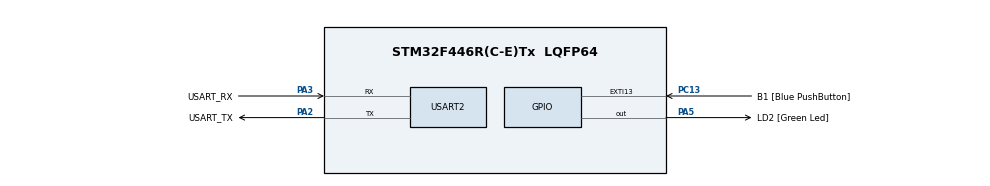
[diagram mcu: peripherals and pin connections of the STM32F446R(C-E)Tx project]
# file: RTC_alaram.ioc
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Mcu.Family=STM32F4
Mcu.Name=STM32F446R(C-E)Tx
Mcu.Package=LQFP64
NVIC.PriorityGroup=NVIC_PRIORITYGROUP_0
NVIC.RTC_Alarm_IRQn=true\:0\:0\:false\:false\:true\:true\:true\:true
PA13.GPIO_Label=TMS
PA13.Mode=Serial_Wire
PA13.Signal=SYS_JTMS-SWDIO
PA14.GPIO_Label=TCK
PA14.Mode=Serial_Wire
PA14.Signal=SYS_JTCK-SWCLK
PA2.GPIO_Label=USART_TX
PA2.Mode=Asynchronous
PA2.Signal=USART2_TX
PA3.GPIO_Label=USART_RX
PA3.Mode=Asynchronous
PA3.Signal=USART2_RX
PA5.GPIO_Label=LD2 [Green Led]
PA5.Signal=GPIO_Output
PB3.GPIO_Label=SWO
PB3.Signal=SYS_JTDO-SWO
PC13.GPIO_Label=B1 [Blue PushButton]
PC13.GPIO_ModeDefaultEXTI=GPIO_MODE_IT_FALLING
PC13.Signal=GPXTI13
PC14-OSC32_IN.Mode=LSE-External-Oscillator
PC14-OSC32_IN.Signal=RCC_OSC32_IN
PC15-OSC32_OUT.Mode=LSE-External-Oscillator
PC15-OSC32_OUT.Signal=RCC_OSC32_OUT
PH0-OSC_IN.Mode=HSE-External-Oscillator
PH0-OSC_IN.Signal=RCC_OSC_IN
PH1-OSC_OUT.Mode=HSE-External-Oscillator
PH1-OSC_OUT.Signal=RCC_OSC_OUT
ProjectManager.HeapSize=0x200
ProjectManager.StackSize=0x400
ProjectManager.TargetToolchain=STM32CubeIDE
RCC.48MHZClocksFreq_Value=84000000
RCC.AHBFreq_Value=80000000
RCC.APB1CLKDivider=RCC_HCLK_DIV2
RCC.APB1Freq_Value=40000000
RCC.APB1TimFreq_Value=80000000
RCC.APB2Freq_Value=80000000
RCC.APB2TimFreq_Value=80000000
RCC.CortexFreq_Value=80000000
RCC.FLatency-AdvancedSettings=FLASH_LATENCY_2
RCC.HCLKFreq_Value=80000000
RCC.HSE_VALUE=8000000
RCC.HSI_VALUE=16000000
RCC.PLLM=4
RCC.PLLN=80
RCC.PLLSourceVirtual=RCC_PLLSOURCE_HSE
RCC.RCC_RTC_Clock_SourceVirtual=RCC_RTCCLKSOURCE_LSE
RCC.SYSCLKFreq_VALUE=80000000
RCC.SYSCLKSource=RCC_SYSCLKSOURCE_PLLCLK
RCC.USBFreq_Value=80000000
RCC.VCOOutputFreq_Value=160000000
RTC.Alarm=RTC_ALARM_A
RTC.Date=24
RTC.Format=RTC_FORMAT_BIN
RTC.Hours=11
RTC.Hours_A=12
RTC.Minutes=46
RTC.Month=RTC_MONTH_SEPTEMBER
RTC.WeekDay=RTC_WEEKDAY_WEDNESDAY
RTC.Year=25
USART2.VirtualMode=VM_ASYNC
VP_RTC_VS_RTC_Activate.Mode=RTC_Enabled
VP_RTC_VS_RTC_Alarm_A_Intern.Mode=Alarm A
VP_RTC_VS_RTC_Calendar.Mode=RTC_Calendar
board=NUCLEO-F446RE

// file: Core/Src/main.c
/* USER CODE BEGIN Header */
/**
  ******************************************************************************
  * @file           : main.c
  * @brief          : Main program body
  ******************************************************************************
  * @attention
  *
  * Copyright (c) 2024 STMicroelectronics.
  * All rights reserved.
  *
  * This software is licensed under terms that can be found in the LICENSE file
  * in the root directory of this software component.
  * If no LICENSE file comes with this software, it is provided AS-IS.
  *
  ******************************************************************************
  */
/* USER CODE END Header */
#include "main.h"
#include <stdio.h>
#include <string.h>

RTC_HandleTypeDef hrtc;

UART_HandleTypeDef huart2;

/* USER CODE BEGIN PV */
uint8_t previous_hour = 0xFF; // Initialize to invalid value for midnight detection
/* USER CODE END PV */

void SystemClock_Config(void);
static void MX_GPIO_Init(void);
static void MX_RTC_Init(void);
static void MX_USART2_UART_Init(void);
/* USER CODE BEGIN PFP */
void UART_Transmit_String(char* str);
/* USER CODE END PFP */

int main(void)
{

  /* MCU Configuration--------------------------------------------------------*/

  /* Reset of all peripherals, Initializes the Flash interface and the Systick. */
  HAL_Init();

  /* Configure the system clock */
  SystemClock_Config();

  /* Initialize all configured peripherals */
  MX_GPIO_Init();
  MX_RTC_Init();
  MX_USART2_UART_Init();
  /* USER CODE BEGIN 2 */

  // Send initial message
  UART_Transmit_String("RTC System Initialized\r\n");

  // Get initial hour for midnight detection
  RTC_TimeTypeDef sTime;
  HAL_RTC_GetTime(&hrtc, &sTime, RTC_FORMAT_BIN);
  previous_hour = sTime.Hours;

  /* USER CODE END 2 */

  /* Infinite loop */
  while (1)
  {

    /* USER CODE BEGIN 3 */
    // Check for midnight rollover in main loop
    RTC_TimeTypeDef current_time;
    HAL_RTC_GetTime(&hrtc, &current_time, RTC_FORMAT_BIN);

    // Detect midnight rollover (23:XX:XX -> 00:XX:XX)
    if (previous_hour == 23 && current_time.Hours == 0) {
        UART_Transmit_String("New Day Started!\r\n");
    }
    previous_hour = current_time.Hours;

    // Enter sleep mode to save power
    HAL_PWR_EnterSLEEPMode(PWR_MAINREGULATOR_ON, PWR_SLEEPENTRY_WFI);
  }
  /* USER CODE END 3 */
}

void SystemClock_Config(void)
{
  RCC_OscInitTypeDef RCC_OscInitStruct = {0};
  RCC_ClkInitTypeDef RCC_ClkInitStruct = {0};
  RCC_PeriphCLKInitTypeDef PeriphClkInitStruct = {0};

  /** Configure the main internal regulator output voltage
  */
  __HAL_RCC_PWR_CLK_ENABLE();
  __HAL_PWR_VOLTAGESCALING_CONFIG(PWR_REGULATOR_VOLTAGE_SCALE3);

  /** Initializes the RCC Oscillators according to the specified parameters
  * in the RCC_OscInitTypeDef structure.
  */
  RCC_OscInitStruct.OscillatorType = RCC_OSCILLATORTYPE_HSI|RCC_OSCILLATORTYPE_LSI;
  RCC_OscInitStruct.HSIState = RCC_HSI_ON;
  RCC_OscInitStruct.HSICalibrationValue = RCC_HSICALIBRATION_DEFAULT;
  RCC_OscInitStruct.LSIState = RCC_LSI_ON;
  RCC_OscInitStruct.PLL.PLLState = RCC_PLL_ON;
  RCC_OscInitStruct.PLL.PLLSource = RCC_PLLSOURCE_HSI;
  RCC_OscInitStruct.PLL.PLLM = 16;
  RCC_OscInitStruct.PLL.PLLN = 336;
  RCC_OscInitStruct.PLL.PLLP = RCC_PLLP_DIV4;
  RCC_OscInitStruct.PLL.PLLQ = 4;
  if (HAL_RCC_OscConfig(&RCC_OscInitStruct) != HAL_OK)
  {
    Error_Handler();
  }

  /** Initializes the CPU, AHB and APB buses clocks
  */
  RCC_ClkInitStruct.ClockType = RCC_CLOCKTYPE_HCLK|RCC_CLOCKTYPE_SYSCLK
                              |RCC_CLOCKTYPE_PCLK1|RCC_CLOCKTYPE_PCLK2;
  RCC_ClkInitStruct.SYSCLKSource = RCC_SYSCLKSOURCE_PLLCLK;
  RCC_ClkInitStruct.AHBCLKDivider = RCC_SYSCLK_DIV1;
  RCC_ClkInitStruct.APB1CLKDivider = RCC_HCLK_DIV2;
  RCC_ClkInitStruct.APB2CLKDivider = RCC_HCLK_DIV1;

  if (HAL_RCC_ClockConfig(&RCC_ClkInitStruct, FLASH_LATENCY_2) != HAL_OK)
  {
    Error_Handler();
  }

  /** PeriphClkInitStruct.PeriphClockSelection = RTC
  */
  PeriphClkInitStruct.PeriphClockSelection = RCC_PERIPHCLK_RTC;
  PeriphClkInitStruct.RTCClockSelection = RCC_RTCCLKSOURCE_LSI;
  if (HAL_RCCEx_PeriphCLKConfig(&PeriphClkInitStruct) != HAL_OK)
  {
    Error_Handler();
  }
}

static void MX_RTC_Init(void)
{

  RTC_TimeTypeDef sTime = {0};
  RTC_DateTypeDef sDate = {0};
  RTC_AlarmTypeDef sAlarm = {0};

  /** Initialize RTC Only
  */
  hrtc.Instance = RTC;
  hrtc.Init.HourFormat = RTC_HOURFORMAT_24;
  hrtc.Init.AsynchPrediv = 127;
  hrtc.Init.SynchPrediv = 255;
  hrtc.Init.OutPut = RTC_OUTPUT_DISABLE;
  hrtc.Init.OutPutPolarity = RTC_OUTPUT_POLARITY_HIGH;
  hrtc.Init.OutPutType = RTC_OUTPUT_TYPE_OPENDRAIN;
  if (HAL_RTC_Init(&hrtc) != HAL_OK)
  {
    Error_Handler();
  }

  /** Initialize RTC and set the Time and Date
  */
  sTime.Hours = 0x12;
  sTime.Minutes = 0x29;
  sTime.Seconds = 0x55;
  sTime.DayLightSaving = RTC_DAYLIGHTSAVING_NONE;
  sTime.StoreOperation = RTC_STOREOPERATION_RESET;
  if (HAL_RTC_SetTime(&hrtc, &sTime, RTC_FORMAT_BCD) != HAL_OK)
  {
    Error_Handler();
  }
  sDate.WeekDay = RTC_WEEKDAY_MONDAY;
  sDate.Month = RTC_MONTH_JANUARY;
  sDate.Date = 0x1;
  sDate.Year = 0x24;

  if (HAL_RTC_SetDate(&hrtc, &sDate, RTC_FORMAT_BCD) != HAL_OK)
  {
    Error_Handler();
  }

  /** Enable the Alarm A
  */
  sAlarm.AlarmTime.Hours = 0x12;
  sAlarm.AlarmTime.Minutes = 0x30;
  sAlarm.AlarmTime.Seconds = 0x0;
  sAlarm.AlarmTime.SubSeconds = 0x0;
  sAlarm.AlarmTime.DayLightSaving = RTC_DAYLIGHTSAVING_NONE;
  sAlarm.AlarmTime.StoreOperation = RTC_STOREOPERATION_RESET;
  sAlarm.AlarmMask = RTC_ALARMMASK_DATEWEEKDAY;
  sAlarm.AlarmSubSecondMask = RTC_ALARMSUBSECONDMASK_ALL;
  sAlarm.AlarmDateWeekDaySel = RTC_ALARMDATEWEEKDAYSEL_DATE;
  sAlarm.AlarmDateWeekDay = 0x1;
  sAlarm.Alarm = RTC_ALARM_A;
  if (HAL_RTC_SetAlarm_IT(&hrtc, &sAlarm, RTC_FORMAT_BCD) != HAL_OK)
  {
    Error_Handler();
  }

  /** Enable the WakeUp
  */
  if (HAL_RTCEx_SetWakeUpTimer_IT(&hrtc, 3999, RTC_WAKEUPCLOCK_RTCCLK_DIV16) != HAL_OK)
  {
    Error_Handler();
  }

}

static void MX_USART2_UART_Init(void)
{

  huart2.Instance = USART2;
  huart2.Init.BaudRate = 115200;
  huart2.Init.WordLength = UART_WORDLENGTH_8B;
  huart2.Init.StopBits = UART_STOPBITS_1;
  huart2.Init.Parity = UART_PARITY_NONE;
  huart2.Init.Mode = UART_MODE_TX_RX;
  huart2.Init.HwFlowCtl = UART_HWCONTROL_NONE;
  huart2.Init.OverSampling = UART_OVERSAMPLING_16;
  if (HAL_UART_Init(&huart2) != HAL_OK)
  {
    Error_Handler();
  }

}

static void MX_GPIO_Init(void)
{
  GPIO_InitTypeDef GPIO_InitStruct = {0};

  /* GPIO Ports Clock Enable */
  __HAL_RCC_GPIOC_CLK_ENABLE();
  __HAL_RCC_GPIOH_CLK_ENABLE();
  __HAL_RCC_GPIOA_CLK_ENABLE();
  __HAL_RCC_GPIOB_CLK_ENABLE();

  /*Configure GPIO pin Output Level */
  HAL_GPIO_WritePin(LD2_GPIO_Port, LD2_Pin, GPIO_PIN_RESET);

  /*Configure GPIO pin : B1_Pin */
  GPIO_InitStruct.Pin = B1_Pin;
  GPIO_InitStruct.Mode = GPIO_MODE_IT_FALLING;
  GPIO_InitStruct.Pull = GPIO_NOPULL;
  HAL_GPIO_Init(B1_GPIO_Port, &GPIO_InitStruct);

  /*Configure GPIO pin : LD2_Pin */
  GPIO_InitStruct.Pin = LD2_Pin;
  GPIO_InitStruct.Mode = GPIO_MODE_OUTPUT_PP;
  GPIO_InitStruct.Pull = GPIO_NOPULL;
  GPIO_InitStruct.Speed = GPIO_SPEED_FREQ_LOW;
  HAL_GPIO_Init(LD2_GPIO_Port, &GPIO_InitStruct);

}

/* USER CODE BEGIN 4 */

/**
  * @brief  UART Transmit String Function
  * @param  str: String to transmit
  * @retval None
  */
void UART_Transmit_String(char* str)
{
    HAL_UART_Transmit(&huart2, (uint8_t*)str, strlen(str), HAL_MAX_DELAY);
}

/**
  * @brief  RTC WakeUp Timer Event Callback
  * @param  hrtc: RTC handle pointer
  * @retval None
  */
void HAL_RTCEx_WakeUpTimerEventCallback(RTC_HandleTypeDef *hrtc)
{
    // Toggle LED on PA5 every 2 seconds
    HAL_GPIO_TogglePin(LD2_GPIO_Port, LD2_Pin);

    // Get and print current time
    RTC_TimeTypeDef sTime;
    RTC_DateTypeDef sDate;
    char time_buffer[50];

    HAL_RTC_GetTime(hrtc, &sTime, RTC_FORMAT_BIN);
    HAL_RTC_GetDate(hrtc, &sDate, RTC_FORMAT_BIN); // Must read date after time to unlock time registers

    // Format and send current time via UART
    sprintf(time_buffer, "Current Time: %02d:%02d:%02d\r\n", sTime.Hours, sTime.Minutes, sTime.Seconds);
    UART_Transmit_String(time_buffer);
}

/**
  * @brief  RTC Alarm A Event Callback
  * @param  hrtc: RTC handle pointer
  * @retval None
  */
void HAL_RTC_AlarmAEventCallback(RTC_HandleTypeDef *hrtc)
{
    // Send alarm message via UART
    UART_Transmit_String("ALARM TRIGGERED!\r\n");
}

/* USER CODE END 4 */

void Error_Handler(void)
{
  __disable_irq();
  while (1)
  {
  }
}
